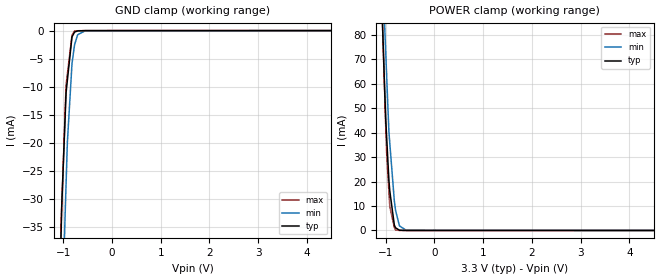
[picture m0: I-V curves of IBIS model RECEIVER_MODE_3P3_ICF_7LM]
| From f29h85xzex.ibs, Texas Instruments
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|WK_PD_ON_3P3_ICF_7LM; WEAK_PULLDOWN_ON
|   Model Cell RECEIVER_MODE_3P3_ICF_7LM
|RECEIVER_MODE_3P3_ICF_7LM
[Model]   RECEIVER_MODE_3P3_ICF_7LM
Model_type   Input
Polarity   Non-Inverting
Vinl = 0.8
Vinh = 2
|   typ   min   max
C_comp   0.213pF   0.2pF   0.23pF
[Model Spec]
Vinl   0.8   0.8   0.8
Vinh   2   2   2
[Temperature Range]   25   155   -40
[Voltage Range]   3.3   2.8   3.63
| Nom Voltages:
|   BIASFET=3.3, VDD=1.2, VDDS=3.3, VSS=0
| Min Voltages:
|   BIASFET=2.8, VDD=1.08, VDDS=2.8, VSS=0
| Max Voltages:
|   BIASFET=3.63, VDD=1.32, VDDS=3.63, VSS=0
[Power Clamp Reference]   3.3   2.8   3.63
[GND Clamp Reference]   0   0   0
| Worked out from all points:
|   GND clamp passes 1 mA (typ) near -0.82 V on its own axis
|   POWER clamp passes 1 mA (typ) near -0.80 V on its own axis
[GND Clamp]
|   Voltage   I(typ)   I(min)   I(max)
-3.3V     -1.431A    -1.17A     -2.111A
-1.057V   -41.25mA   -63.95mA   -38.9mA
-1.049V   -37.93mA   -60.94mA   -35.77mA
-1.032V   -31.34mA   -54.13mA   -31.54mA
-1.014V   -27.25mA   -47.78mA   -27.28mA
-942.5mV  -11.09mA   -27.44mA   -9.753mA
-916.1mV  -8.881mA   -19.97mA   -7.815mA
-821mV    -1.121mA   -5.914mA   -830.2uA
-768mV    -261.7uA   -2.514mA   -65.21uA
-704.1mV  -58.23uA   -740.9uA   -31.27uA
-547.6mV  -10.53uA   -23.63uA   -1.742uA
6.6V      0A         0A         0A
[POWER Clamp]
|   Voltage   I(typ)   I(min)   I(max)
-3.3V     1.901A     2.211A     2.057A
-1.072V   87.53mA    117.4mA    87.59mA
-1.025V   58.99mA    84.95mA    58.07mA
-1.002V   45.88mA    73.4mA     43.43mA
-981.1mV  37.85mA    62.95mA    31.29mA
-935.5mV  20.45mA    40.3mA     15.82mA
-917.9mV  16.22mA    35.82mA    9.822mA
-824.6mV  2.253mA    12.17mA    1.251mA
-800.1mV  1.104mA    8.358mA    177uA
-718.8mV  103.6uA    1.86mA     19.79uA
-578.1mV  11.49uA    63.61uA    689.8nA
6.6V      0A         0A         0A
